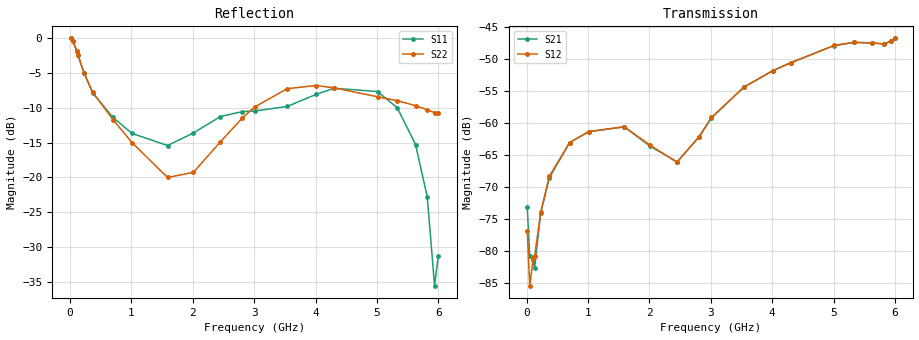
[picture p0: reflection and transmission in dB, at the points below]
!Agilent Technologies,N5230A,MY45001650,A.07.50.48
!Agilent N5230A: A.07.50.48
!Date: Saturday, July 08, 2017 15:59:01
!Correction: S11(Full 2 Port(1,2))
!S21(Full 2 Port(1,2))
!S12(Full 2 Port(1,2))
!S22(Full 2 Port(1,2))
!S2P File: Measurements: S11, S21, S12, S22:
# Hz S  dB  R 50
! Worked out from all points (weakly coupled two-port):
!   600 points, 10 MHz to 6 GHz, reference 50 ohm
!   highest |S21| = -46.71 dB at 6 GHz (marker M1); lowest = -82.7 dB at 130 MHz (marker M2)
!   lowest |S11| = -35.5 dB at 5.94 GHz (marker M3), VSWR 1.03, Z = 48.6 - j0.925 ohm
!   |S11| at or under -10 dB: 543.7 MHz to 3.501 GHz (2.958 GHz wide, 146 % of centre); 5.329 GHz to end of sweep
!   |S22| runs from -20.7 to -0.1 dB; largest |S21 - S12| = 0.0003
!   S11 on the Smith chart (normalised r, x): 10 MHz: 2, -19; 110 MHz: 0.49, -1.80; 370 MHz: 0.53, -0.43; 2.81 GHz: 0.59, +0.25; 4.3 GHz: 2.42, +0.49; 6 GHz: 0.97, +0.04
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1e7  -0.11 -6.0  -73.05 27.2  -76.81 -80.0  -0.11 -5.7
5e7  -0.52 -27.8  -80.70 160.3  -85.38 157.4  -0.50 -26.5
1.1e8  -1.94 -55.4  -81.44 130.7  -80.99 138.0  -1.90 -52.8
1.3e8  -2.50 -62.9  -82.66 133.9  -80.74 141.1  -2.47 -59.9
2.3e8  -5.09 -93.0  -73.96 115.7  -73.90 119.9  -5.05 -88.1
3.7e8  -7.90 -121.7  -68.53 87.0  -68.24 88.2  -7.84 -113.4
7e8  -11.40 -164.1  -63.00 53.2  -63.00 53.4  -11.71 -148.3
1.01e9  -13.70 176.2  -61.31 22.9  -61.28 22.5  -15.01 -165.5
1.59e9  -15.43 168.7  -60.54 -28.0  -60.52 -27.4  -20.00 -179.6
2.01e9  -13.64 172.0  -63.57 -75.3  -63.40 -75.2  -19.27 -174.9
2.45e9  -11.29 158.3  -66.00 -163.7  -66.07 -163.1  -14.91 173.3
2.81e9  -10.57 139.9  -62.14 123.7  -62.05 124.6  -11.48 160.9
3.01e9  -10.50 124.0  -59.17 95.4  -59.07 95.4  -9.91 152.7
3.54e9  -9.84 73.9  -54.32 48.7  -54.32 48.8  -7.30 135.8
4.01e9  -8.12 29.6  -51.76 7.9  -51.76 8.1  -6.85 119.0
4.3e9  -7.24 11.0  -50.53 -10.5  -50.52 -10.5  -7.18 107.8
5.01e9  -7.71 -22.5  -47.82 -61.8  -47.81 -61.7  -8.46 69.8
5.33e9  -10.01 -37.2  -47.34 -90.0  -47.33 -90.0  -9.01 49.8
5.63e9  -15.29 -53.7  -47.39 -111.4  -47.42 -111.4  -9.74 30.8
5.82e9  -22.76 -69.2  -47.61 -119.3  -47.57 -119.1  -10.32 18.6
5.94e9  -35.47 -145.6  -47.14 -124.8  -47.11 -124.8  -10.74 12.4
6e9  -31.23 125.6  -46.71 -128.7  -46.70 -128.5  -10.82 9.3
